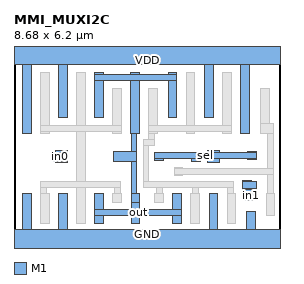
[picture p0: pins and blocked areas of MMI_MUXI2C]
MACRO MMI_MUXI2C
	CLASS CORE ;
	FOREIGN MMI_MUXI2C 0 0 ;
	SIZE 8.68 BY 6.2 ;
	SYMMETRY X Y ;
	SITE CORE1 ;
	PIN out
		DIRECTION output ;
		USE SIGNAL ;
		PORT
			LAYER M1 ;
			RECT 2.635 5.455 2.915 5.53 ;
			LAYER M1 ;
			RECT 3.815 5.455 4.095 5.53 ;
			LAYER M1 ;
			RECT 5.035 5.455 5.315 5.53 ;
			LAYER M1 ;
			RECT 2.635 5.265 5.315 5.455 ;
			LAYER M1 ;
			RECT 2.635 4.075 2.915 5.265 ;
			LAYER M1 ;
			RECT 3.815 3.545 4.095 5.265 ;
			LAYER M1 ;
			RECT 5.035 4.075 5.315 5.265 ;
			LAYER M1 ;
			RECT 3.82 2.955 4.01 3.545 ;
			LAYER M1 ;
			RECT 3.245 2.625 4.01 2.955 ;
			LAYER M1 ;
			RECT 3.82 1.575 4.01 2.625 ;
			LAYER M1 ;
			RECT 2.635 1.06 2.915 1.575 ;
			LAYER M1 ;
			RECT 3.82 1.3 4.11 1.575 ;
			LAYER M1 ;
			RECT 3.83 1.06 4.11 1.3 ;
			LAYER M1 ;
			RECT 5.185 1.06 5.465 1.575 ;
			LAYER M1 ;
			RECT 2.635 0.87 5.465 1.06 ;
			LAYER M1 ;
			RECT 2.635 0.62 2.915 0.87 ;
			LAYER M1 ;
			RECT 3.83 0.62 4.11 0.87 ;
			LAYER M1 ;
			RECT 5.185 0.62 5.465 0.87 ;
		END
		AntennaDiffArea 4.101525 ;
	END out
	PIN in1
		DIRECTION input ;
		USE SIGNAL ;
		PORT
			LAYER M1 ;
			RECT 7.465 1.98 7.745 2.01 ;
			LAYER M1 ;
			RECT 7.465 1.73 7.925 1.98 ;
			LAYER M1 ;
			RECT 7.47 1.705 7.925 1.73 ;
			LAYER M1 ;
			RECT 7.57 1.36 7.925 1.705 ;
		END
		AntennaGateArea 1.386 ;
	END in1
	PIN sel
		DIRECTION input ;
		USE SIGNAL ;
		PORT
			LAYER M1 ;
			RECT 6.32 2.935 6.7 2.98 ;
			LAYER M1 ;
			RECT 7.63 2.935 7.91 2.965 ;
			LAYER M1 ;
			RECT 4.695 2.93 7.91 2.935 ;
			LAYER M1 ;
			RECT 4.6 2.74 7.91 2.93 ;
			LAYER M1 ;
			RECT 4.6 2.65 4.88 2.74 ;
			LAYER M1 ;
			RECT 5.8 2.63 6.08 2.74 ;
			LAYER M1 ;
			RECT 6.32 2.6 6.7 2.74 ;
			LAYER M1 ;
			RECT 7.63 2.685 7.91 2.74 ;
		END
		AntennaGateArea 1.7325 ;
	END sel
	PIN GND
		DIRECTION inout ;
		USE GROUND ;
		PORT
			LAYER M1 ;
			RECT 0.275 0.42 0.555 1.575 ;
			LAYER M1 ;
			RECT 1.455 0.42 1.735 1.575 ;
			LAYER M1 ;
			RECT 6.365 0.42 6.645 1.575 ;
			LAYER M1 ;
			RECT 7.6 0.42 7.88 0.99 ;
			LAYER M1 ;
			RECT 0 -0.42 8.68 0.42 ;
		END
	END GND
	PIN VDD
		DIRECTION inout ;
		USE POWER ;
		PORT
			LAYER M1 ;
			RECT 0 5.78 8.68 6.62 ;
			LAYER M1 ;
			RECT 0.275 3.545 0.555 5.78 ;
			LAYER M1 ;
			RECT 1.455 4.075 1.735 5.78 ;
			LAYER M1 ;
			RECT 6.215 4.075 6.495 5.78 ;
			LAYER M1 ;
			RECT 7.395 3.545 7.675 5.78 ;
		END
	END VDD
	PIN in0
		DIRECTION input ;
		USE SIGNAL ;
		PORT
			LAYER M1 ;
			RECT 1.36 2.915 1.74 2.98 ;
			LAYER M1 ;
			RECT 1.275 2.635 1.74 2.915 ;
			LAYER M1 ;
			RECT 1.36 2.6 1.74 2.635 ;
		END
		AntennaGateArea 1.386 ;
	END in0
	OBS
		LAYER M1 ;
		RECT 0.865 3.8 1.145 5.53 ;
		LAYER M1 ;
		RECT 2.045 3.8 2.325 5.53 ;
		LAYER M1 ;
		RECT 3.225 3.8 3.505 4.995 ;
		LAYER M1 ;
		RECT 0.865 3.61 3.505 3.8 ;
		LAYER M1 ;
		RECT 0.865 3.545 1.145 3.61 ;
		LAYER M1 ;
		RECT 2.045 1.985 2.325 3.61 ;
		LAYER M1 ;
		RECT 3.225 3.545 3.505 3.61 ;
		LAYER M1 ;
		RECT 4.405 3.795 4.685 4.995 ;
		LAYER M1 ;
		RECT 5.625 3.795 5.905 5.53 ;
		LAYER M1 ;
		RECT 6.805 3.795 7.085 5.53 ;
		LAYER M1 ;
		RECT 4.405 3.605 7.085 3.795 ;
		LAYER M1 ;
		RECT 4.405 3.545 4.685 3.605 ;
		LAYER M1 ;
		RECT 5.625 3.545 5.905 3.605 ;
		LAYER M1 ;
		RECT 6.805 3.545 7.085 3.605 ;
		LAYER M1 ;
		RECT 8.045 3.88 8.325 5.015 ;
		LAYER M1 ;
		RECT 8.045 3.545 8.465 3.88 ;
		LAYER M1 ;
		RECT 4.405 3.34 4.595 3.545 ;
		LAYER M1 ;
		RECT 0.87 1.79 3.47 1.985 ;
		LAYER M1 ;
		RECT 0.87 1.575 1.06 1.79 ;
		LAYER M1 ;
		RECT 0.865 0.62 1.145 1.575 ;
		LAYER M1 ;
		RECT 2.045 0.62 2.325 1.79 ;
		LAYER M1 ;
		RECT 3.275 1.575 3.47 1.79 ;
		LAYER M1 ;
		RECT 4.21 3.15 4.595 3.34 ;
		LAYER M1 ;
		RECT 4.21 1.965 4.4 3.15 ;
		LAYER M1 ;
		RECT 5.225 2.4 5.505 2.445 ;
		LAYER M1 ;
		RECT 8.27 2.4 8.465 3.545 ;
		LAYER M1 ;
		RECT 5.225 2.21 8.465 2.4 ;
		LAYER M1 ;
		RECT 5.225 2.165 5.505 2.21 ;
		LAYER M1 ;
		RECT 4.21 1.775 7.15 1.965 ;
		LAYER M1 ;
		RECT 4.635 1.575 4.83 1.775 ;
		LAYER M1 ;
		RECT 5.82 1.575 6.015 1.775 ;
		LAYER M1 ;
		RECT 6.955 1.575 7.15 1.775 ;
		LAYER M1 ;
		RECT 3.225 1.29 3.505 1.575 ;
		LAYER M1 ;
		RECT 4.595 1.29 4.875 1.575 ;
		LAYER M1 ;
		RECT 5.775 0.62 6.055 1.575 ;
		LAYER M1 ;
		RECT 6.955 0.62 7.235 1.575 ;
		LAYER M1 ;
		RECT 8.27 1.575 8.465 2.21 ;
		LAYER M1 ;
		RECT 8.23 0.875 8.51 1.575 ;
	END
END MMI_MUXI2C
